VERSION 5.7 ;
  NOWIREEXTENSIONATPIN ON ;
  DIVIDERCHAR "/" ;
  BUSBITCHARS "[]" ;
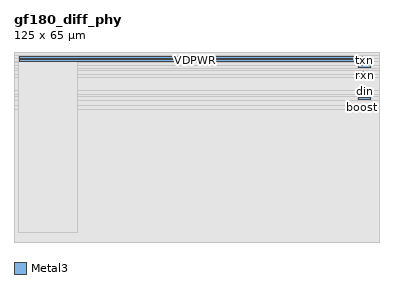
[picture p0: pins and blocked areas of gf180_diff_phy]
MACRO gf180_diff_phy
  CLASS BLOCK ;
  FOREIGN gf180_diff_phy ;
  ORIGIN 0.000 0.000 ;
  SIZE 125.000 BY 65.000 ;
  PIN din
    DIRECTION INPUT ;
    USE SIGNAL ;
    ANTENNAGATEAREA 3.920000 ;
    PORT
      LAYER Metal3 ;
        RECT 118.000 48.700 122.000 49.300 ;
    END
  END din
  PIN boost
    DIRECTION INPUT ;
    USE SIGNAL ;
    ANTENNAGATEAREA 10.639999 ;
    PORT
      LAYER Metal3 ;
        RECT 118.000 45.700 122.000 46.300 ;
    END
  END boost
  PIN rxp
    DIRECTION INPUT ;
    USE SIGNAL ;
    ANTENNAGATEAREA 24.000000 ;
    PORT
      LAYER Metal3 ;
        RECT 118.000 57.700 122.000 58.300 ;
    END
  END rxp
  PIN rxn
    DIRECTION INPUT ;
    USE SIGNAL ;
    ANTENNAGATEAREA 24.000000 ;
    PORT
      LAYER Metal3 ;
        RECT 118.000 56.700 122.000 57.300 ;
    END
  END rxn
  PIN txp
    DIRECTION OUTPUT ;
    USE SIGNAL ;
    PORT
      LAYER Metal3 ;
        RECT 118.000 60.700 122.000 61.300 ;
    END
  END txp
  PIN txn
    DIRECTION OUTPUT ;
    USE SIGNAL ;
    PORT
      LAYER Metal3 ;
        RECT 118.000 59.700 122.000 60.300 ;
    END
  END txn
  PIN dout
    DIRECTION OUTPUT ;
    USE SIGNAL ;
    ANTENNADIFFAREA 9.170000 ;
    PORT
      LAYER Metal3 ;
        RECT 118.000 50.700 122.000 51.300 ;
    END
  END dout
  PIN VDPWR
    DIRECTION INOUT ;
    USE POWER ;
    PORT
      LAYER Metal3 ;
        RECT 2.000 61.700 122.000 62.300 ;
    END
  END VDPWR
  PIN VGND
    DIRECTION INOUT ;
    USE GROUND ;
    PORT
      LAYER Metal3 ;
        RECT 2.000 62.700 122.000 63.300 ;
    END
  END VGND
  OBS
    LAYER Metal1 ;
      RECT 0.000 0.000 125.000 65.000 ;
    LAYER Metal2 ;
      RECT 0.000 0.000 125.000 65.000 ;
    LAYER Metal3 ;
      RECT 0.000 0.000 125.000 45.300 ;
      RECT 0.000 46.700 125.000 48.300 ;
      RECT 0.000 45.300 117.600 46.700 ;
      RECT 122.400 45.300 125.000 46.700 ;
      RECT 0.000 49.700 125.000 50.300 ;
      RECT 0.000 51.700 125.000 56.300 ;
      RECT 0.000 50.300 117.600 51.700 ;
      RECT 122.400 50.300 125.000 51.700 ;
      RECT 0.000 56.300 117.600 57.300 ;
      RECT 122.400 56.300 125.000 57.300 ;
      RECT 0.000 58.700 125.000 59.300 ;
      RECT 0.000 59.300 117.600 60.300 ;
      RECT 122.400 59.300 125.000 60.300 ;
      RECT 0.000 63.700 125.000 65.000 ;
      RECT 0.000 62.700 1.600 63.700 ;
      RECT 122.400 62.700 125.000 63.700 ;
      RECT 0.000 61.700 1.600 62.700 ;
      RECT 122.400 61.700 125.000 62.700 ;
      RECT 0.000 60.300 117.600 61.300 ;
      RECT 0.000 61.300 1.600 61.700 ;
      RECT 122.400 60.300 125.000 61.700 ;
      RECT 0.000 57.300 117.600 58.700 ;
      RECT 122.400 57.300 125.000 58.700 ;
      RECT 0.000 48.300 117.600 49.700 ;
      RECT 122.400 48.300 125.000 49.700 ;
    LAYER Metal4 ;
      RECT 1.400 3.400 21.600 63.600 ;
  END
END gf180_diff_phy
END LIBRARY

